One B-rep face of a CAD part: STEP entity #417.
In plain terms, the planar face has unit normal (1, 0, 0).
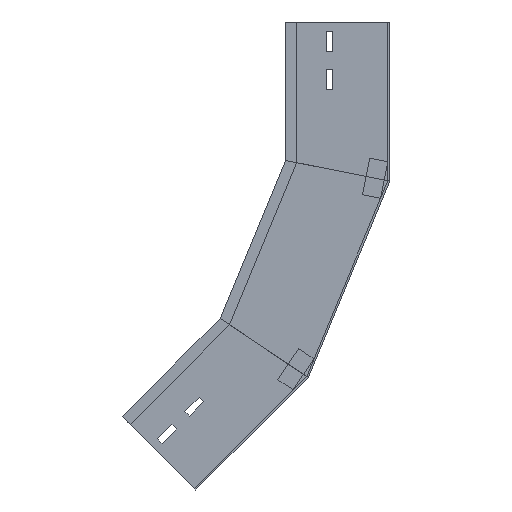
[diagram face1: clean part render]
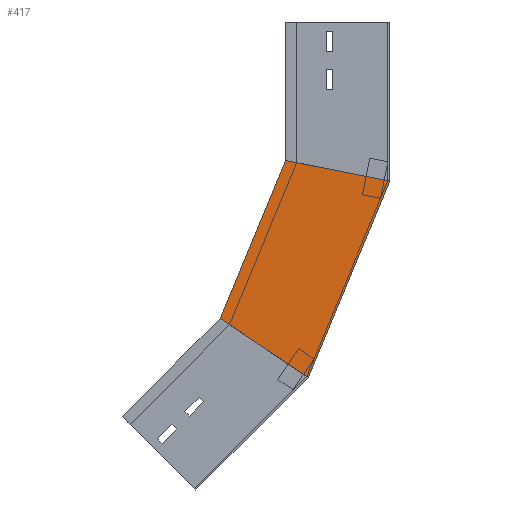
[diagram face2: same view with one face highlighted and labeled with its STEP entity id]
Its self-contained STEP definition (entity closure, numbers rounded to 3 decimals):
#11 = CARTESIAN_POINT ( 'NONE',  ( 0., 0., -172.1 ) ) ;
#56 = DIRECTION ( 'NONE',  ( 0., -0.981, -0.195 ) ) ;
#77 = DIRECTION ( 'NONE',  ( 0., 0.383, -0.924 ) ) ;
#147 = EDGE_CURVE ( 'NONE', #846, #657, #238, .T. ) ;
#237 = AXIS2_PLACEMENT_3D ( 'NONE', #650, #1118, #1006 ) ;
#238 = LINE ( 'NONE', #1152, #527 ) ;
#286 = ORIENTED_EDGE ( 'NONE', *, *, #902, .T. ) ;
#417 = ADVANCED_FACE ( 'NONE', ( #1345 ), #551, .F. ) ;
#419 = CARTESIAN_POINT ( 'NONE',  ( 0., 32.93, -165.55 ) ) ;
#482 = DIRECTION ( 'NONE',  ( 0., 0.383, -0.924 ) ) ;
#505 = ORIENTED_EDGE ( 'NONE', *, *, #147, .F. ) ;
#527 = VECTOR ( 'NONE', #482, 1000. ) ;
#551 = PLANE ( 'NONE',  #237 ) ;
#581 = VECTOR ( 'NONE', #56, 1000. ) ;
#601 = EDGE_CURVE ( 'NONE', #657, #688, #1269, .T. ) ;
#613 = VERTEX_POINT ( 'NONE', #11 ) ;
#633 = LINE ( 'NONE', #419, #581 ) ;
#650 = CARTESIAN_POINT ( 'NONE',  ( 0., 0., -172.1 ) ) ;
#657 = VERTEX_POINT ( 'NONE', #703 ) ;
#684 = CARTESIAN_POINT ( 'NONE',  ( 0., 125.326, -359.663 ) ) ;
#688 = VERTEX_POINT ( 'NONE', #1069 ) ;
#703 = CARTESIAN_POINT ( 'NONE',  ( 0., 183.39, -320.866 ) ) ;
#733 = CARTESIAN_POINT ( 'NONE',  ( 0., 0., -172.1 ) ) ;
#762 = CARTESIAN_POINT ( 'NONE',  ( 0., 112.5, -149.722 ) ) ;
#798 = VECTOR ( 'NONE', #1157, 1000. ) ;
#846 = VERTEX_POINT ( 'NONE', #762 ) ;
#902 = EDGE_CURVE ( 'NONE', #846, #613, #633, .T. ) ;
#1006 = DIRECTION ( 'NONE',  ( 0., 0., 1. ) ) ;
#1020 = ORIENTED_EDGE ( 'NONE', *, *, #1110, .T. ) ;
#1043 = ORIENTED_EDGE ( 'NONE', *, *, #601, .F. ) ;
#1060 = EDGE_LOOP ( 'NONE', ( #505, #286, #1020, #1043 ) ) ;
#1069 = CARTESIAN_POINT ( 'NONE',  ( 0., 88.017, -384.592 ) ) ;
#1110 = EDGE_CURVE ( 'NONE', #613, #688, #1309, .T. ) ;
#1118 = DIRECTION ( 'NONE',  ( -1., 0., 0. ) ) ;
#1152 = CARTESIAN_POINT ( 'NONE',  ( 0., 103.936, -129.048 ) ) ;
#1157 = DIRECTION ( 'NONE',  ( 0., -0.831, -0.556 ) ) ;
#1269 = LINE ( 'NONE', #684, #798 ) ;
#1309 = LINE ( 'NONE', #733, #1347 ) ;
#1345 = FACE_OUTER_BOUND ( 'NONE', #1060, .T. ) ;
#1347 = VECTOR ( 'NONE', #77, 1000. ) ;
